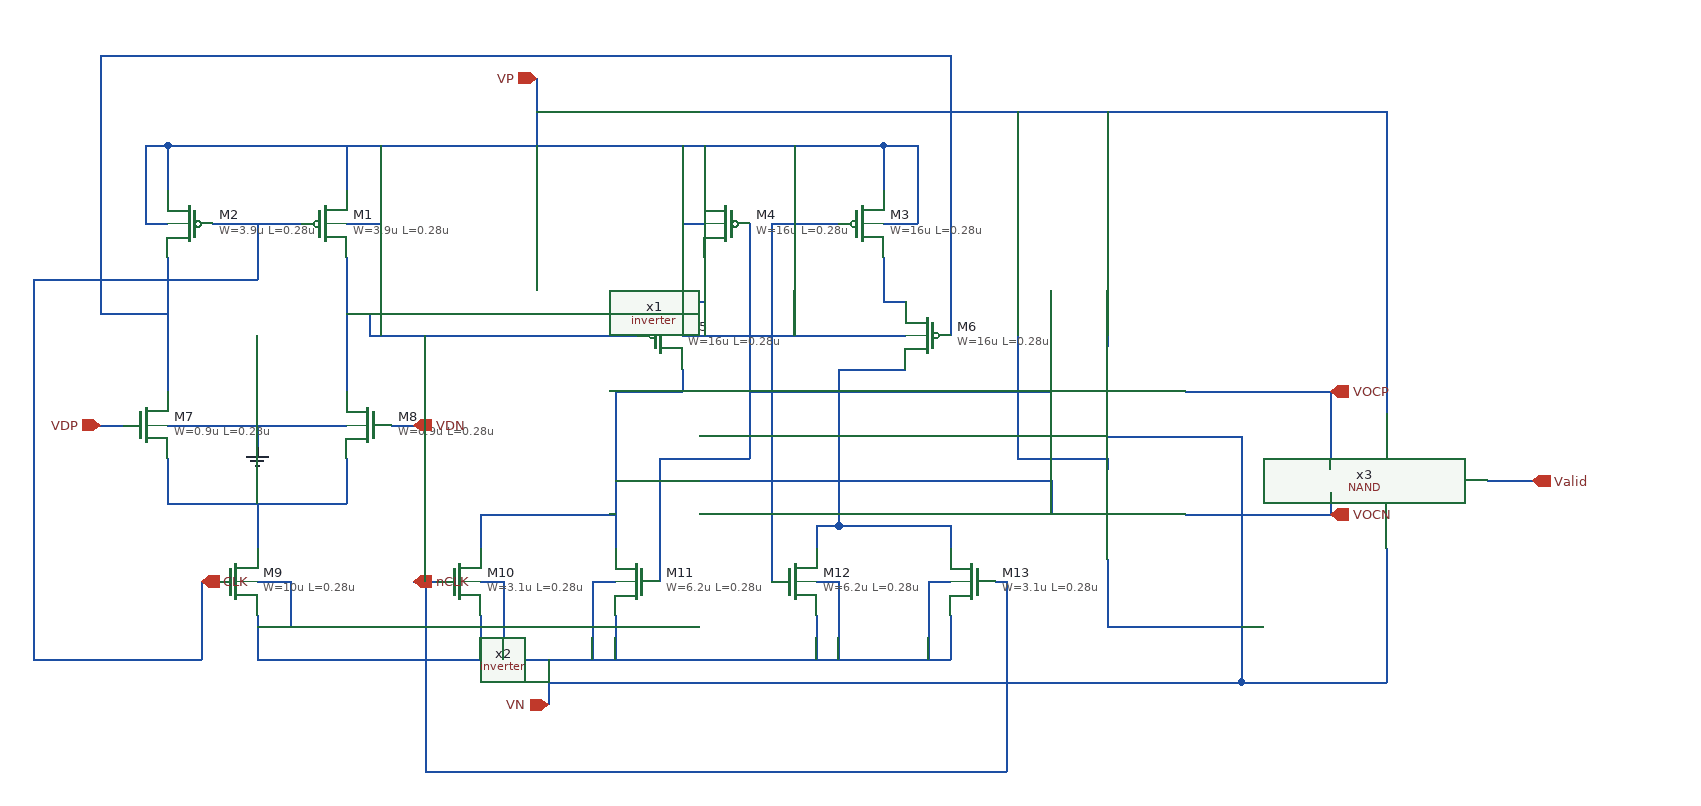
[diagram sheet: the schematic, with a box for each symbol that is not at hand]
v {xschem version=3.4.8RC file_version=1.2}
G {}
K {}
V {}
S {}
E {}
N 380 -920 380 -880 {lab=VP}
N 380 -920 1020 -920 {lab=VP}
N 1020 -920 1020 -880 {lab=VP}
N 540 -920 540 -880 {lab=VP}
N 540 -850 570 -850 {lab=VP}
N 570 -920 570 -850 {lab=VP}
N 860 -920 860 -880 {lab=VP}
N 840 -850 860 -850 {lab=VP}
N 840 -920 840 -850 {lab=VP}
N 1020 -850 1050 -850 {lab=VP}
N 1050 -920 1050 -850 {lab=VP}
N 1020 -920 1050 -920 {lab=VP}
N 710 -980 710 -920 {lab=VP}
N 840 -780 860 -780 {lab=#net1}
N 860 -820 860 -780 {lab=#net1}
N 1020 -820 1020 -780 {lab=#net2}
N 1020 -780 1040 -780 {lab=#net2}
N 420 -850 500 -850 {lab=CLK}
N 460 -850 460 -820 {lab=CLK}
N 380 -820 380 -700 {lab=#net3}
N 540 -820 540 -700 {lab=#net4}
N 380 -640 380 -600 {lab=#net5}
N 380 -600 540 -600 {lab=#net5}
N 540 -640 540 -600 {lab=#net5}
N 460 -600 460 -560 {lab=#net5}
N 460 -530 490 -530 {lab=VN}
N 490 -530 490 -490 {lab=VN}
N 460 -490 490 -490 {lab=VN}
N 460 -500 460 -460 {lab=VN}
N 660 -500 660 -460 {lab=VN}
N 780 -500 780 -460 {lab=VN}
N 960 -500 960 -460 {lab=VN}
N 1080 -500 1080 -460 {lab=VN}
N 460 -460 1080 -460 {lab=VN}
N 900 -850 900 -640 {lab=#net6}
N 820 -640 900 -640 {lab=#net6}
N 820 -640 820 -530 {lab=#net6}
N 920 -850 980 -850 {lab=#net7}
N 920 -850 920 -530 {lab=#net7}
N 720 -460 720 -420 {lab=VN}
N 760 -530 780 -530 {lab=VN}
N 760 -530 760 -460 {lab=VN}
N 660 -530 680 -530 {lab=VN}
N 680 -530 680 -460 {lab=VN}
N 960 -530 980 -530 {lab=VN}
N 980 -530 980 -460 {lab=VN}
N 1060 -530 1080 -530 {lab=VN}
N 1060 -530 1060 -460 {lab=VN}
N 840 -720 840 -700 {lab=#net7}
N 780 -700 840 -700 {lab=#net7}
N 780 -700 780 -560 {lab=#net7}
N 660 -590 660 -560 {lab=#net7}
N 660 -590 780 -590 {lab=#net7}
N 980 -720 1040 -720 {lab=#net6}
N 980 -720 980 -580 {lab=#net6}
N 960 -580 980 -580 {lab=#net6}
N 960 -580 960 -560 {lab=#net6}
N 980 -580 1080 -580 {lab=#net6}
N 1080 -580 1080 -560 {lab=#net6}
N 380 -670 540 -670 {lab=GND}
N 460 -670 460 -650 {lab=GND}
N 840 -750 1040 -750 {lab=VP}
N 1120 -530 1130 -530 {lab=nCLK}
N 410 -530 420 -530 {lab=CLK}
N 600 -530 620 -530 {lab=nCLK}
N 580 -670 600 -670 {lab=VDN}
N 320 -670 340 -670 {lab=VDP}
N 900 -700 980 -700 {lab=#net6}
N 980 -700 1170 -700 {lab=#net6}
N 780 -620 920 -620 {lab=#net7}
N 920 -620 1170 -620 {lab=#net7}
N 360 -770 380 -770 {lab=#net3}
N 540 -770 560 -770 {lab=#net4}
N 360 -850 380 -850 {lab=VP}
N 360 -920 360 -850 {lab=VP}
N 360 -920 380 -920 {lab=VP}
N 940 -920 940 -750 {lab=VP}
N 710 -950 1350 -950 {lab=VP}
N 610 -530 610 -360 {lab=nCLK}
N 610 -360 1130 -360 {lab=nCLK}
N 1130 -530 1130 -360 {lab=nCLK}
N 410 -530 410 -460 {lab=CLK}
N 260 -460 410 -460 {lab=CLK}
N 260 -800 260 -460 {lab=CLK}
N 260 -800 440 -800 {lab=CLK}
N 560 -770 560 -750 {lab=#net4}
N 320 -770 360 -770 {lab=#net3}
N 320 -1000 320 -770 {lab=#net3}
N 440 -800 460 -800 {lab=CLK}
N 460 -820 460 -800 {lab=CLK}
N 1170 -620 1170 -590 {lab=#net7}
N 1220 -950 1220 -740 {lab=VP}
N 1220 -640 1220 -630 {lab=VP}
N 1160 -640 1220 -640 {lab=VP}
N 1140 -640 1160 -640 {lab=VP}
N 1140 -950 1140 -640 {lab=VP}
N 1220 -660 1340 -660 {lab=VN}
N 1340 -660 1340 -440 {lab=VN}
N 1220 -550 1220 -490 {lab=VN}
N 1220 -490 1340 -490 {lab=VN}
N 720 -440 1340 -440 {lab=VN}
N 1290 -700 1420 -700 {lab=VOCP}
N 1420 -700 1420 -630 {lab=VOCP}
N 1290 -590 1420 -590 {lab=VOCN}
N 1420 -610 1420 -590 {lab=VOCN}
N 1560 -620 1600 -620 {lab=Valid}
N 1470 -950 1470 -680 {lab=VP}
N 1350 -950 1470 -950 {lab=VP}
N 1470 -560 1470 -440 {lab=VN}
N 1340 -440 1470 -440 {lab=VN}
N 560 -750 670 -750 {lab=#net4}
N 320 -1000 800 -1000 {lab=#net3}
N 670 -750 800 -750 {lab=#net4}
N 800 -1000 1080 -1000 {lab=#net3}
N 1080 -1000 1080 -750 {lab=#net3}
C {symbols/pfet_03v3.sym} 520 -850 0 0 {name=M1
L=0.28u
W=3.9u
nf=1
m=1
ad="'int((nf+1)/2) * W/nf * 0.18u'"
pd="'2*int((nf+1)/2) * (W/nf + 0.18u)'"
as="'int((nf+2)/2) * W/nf * 0.18u'"
ps="'2*int((nf+2)/2) * (W/nf + 0.18u)'"
nrd="'0.18u / W'" nrs="'0.18u / W'"
sa=0 sb=0 sd=0
model=pfet_03v3
spiceprefix=X
}
C {symbols/pfet_03v3.sym} 400 -850 0 1 {name=M2
L=0.28u
W=3.9u
nf=1
m=1
ad="'int((nf+1)/2) * W/nf * 0.18u'"
pd="'2*int((nf+1)/2) * (W/nf + 0.18u)'"
as="'int((nf+2)/2) * W/nf * 0.18u'"
ps="'2*int((nf+2)/2) * (W/nf + 0.18u)'"
nrd="'0.18u / W'" nrs="'0.18u / W'"
sa=0 sb=0 sd=0
model=pfet_03v3
spiceprefix=X
}
C {symbols/pfet_03v3.sym} 1000 -850 0 0 {name=M3
L=0.28u
W=16u
nf=1
m=1
ad="'int((nf+1)/2) * W/nf * 0.18u'"
pd="'2*int((nf+1)/2) * (W/nf + 0.18u)'"
as="'int((nf+2)/2) * W/nf * 0.18u'"
ps="'2*int((nf+2)/2) * (W/nf + 0.18u)'"
nrd="'0.18u / W'" nrs="'0.18u / W'"
sa=0 sb=0 sd=0
model=pfet_03v3
spiceprefix=X
}
C {symbols/pfet_03v3.sym} 880 -850 0 1 {name=M4
L=0.28u
W=16u
nf=1
m=1
ad="'int((nf+1)/2) * W/nf * 0.18u'"
pd="'2*int((nf+1)/2) * (W/nf + 0.18u)'"
as="'int((nf+2)/2) * W/nf * 0.18u'"
ps="'2*int((nf+2)/2) * (W/nf + 0.18u)'"
nrd="'0.18u / W'" nrs="'0.18u / W'"
sa=0 sb=0 sd=0
model=pfet_03v3
spiceprefix=X
}
C {symbols/pfet_03v3.sym} 820 -750 0 0 {name=M5
L=0.28u
W=16u
nf=1
m=1
ad="'int((nf+1)/2) * W/nf * 0.18u'"
pd="'2*int((nf+1)/2) * (W/nf + 0.18u)'"
as="'int((nf+2)/2) * W/nf * 0.18u'"
ps="'2*int((nf+2)/2) * (W/nf + 0.18u)'"
nrd="'0.18u / W'" nrs="'0.18u / W'"
sa=0 sb=0 sd=0
model=pfet_03v3
spiceprefix=X
}
C {symbols/pfet_03v3.sym} 1060 -750 0 1 {name=M6
L=0.28u
W=16u
nf=1
m=1
ad="'int((nf+1)/2) * W/nf * 0.18u'"
pd="'2*int((nf+1)/2) * (W/nf + 0.18u)'"
as="'int((nf+2)/2) * W/nf * 0.18u'"
ps="'2*int((nf+2)/2) * (W/nf + 0.18u)'"
nrd="'0.18u / W'" nrs="'0.18u / W'"
sa=0 sb=0 sd=0
model=pfet_03v3
spiceprefix=X
}
C {symbols/nfet_03v3.sym} 360 -670 0 0 {name=M7
L=0.28u
W=0.9u
nf=1
m=1
ad="'int((nf+1)/2) * W/nf * 0.18u'"
pd="'2*int((nf+1)/2) * (W/nf + 0.18u)'"
as="'int((nf+2)/2) * W/nf * 0.18u'"
ps="'2*int((nf+2)/2) * (W/nf + 0.18u)'"
nrd="'0.18u / W'" nrs="'0.18u / W'"
sa=0 sb=0 sd=0
model=nfet_03v3
spiceprefix=X
}
C {symbols/nfet_03v3.sym} 560 -670 0 1 {name=M8
L=0.28u
W=0.9u
nf=1
m=1
ad="'int((nf+1)/2) * W/nf * 0.18u'"
pd="'2*int((nf+1)/2) * (W/nf + 0.18u)'"
as="'int((nf+2)/2) * W/nf * 0.18u'"
ps="'2*int((nf+2)/2) * (W/nf + 0.18u)'"
nrd="'0.18u / W'" nrs="'0.18u / W'"
sa=0 sb=0 sd=0
model=nfet_03v3
spiceprefix=X
}
C {symbols/nfet_03v3.sym} 440 -530 0 0 {name=M9
L=0.28u
W=10u
nf=1
m=1
ad="'int((nf+1)/2) * W/nf * 0.18u'"
pd="'2*int((nf+1)/2) * (W/nf + 0.18u)'"
as="'int((nf+2)/2) * W/nf * 0.18u'"
ps="'2*int((nf+2)/2) * (W/nf + 0.18u)'"
nrd="'0.18u / W'" nrs="'0.18u / W'"
sa=0 sb=0 sd=0
model=nfet_03v3
spiceprefix=X
}
C {symbols/nfet_03v3.sym} 640 -530 0 0 {name=M10
L=0.28u
W=3.1u
nf=1
m=1
ad="'int((nf+1)/2) * W/nf * 0.18u'"
pd="'2*int((nf+1)/2) * (W/nf + 0.18u)'"
as="'int((nf+2)/2) * W/nf * 0.18u'"
ps="'2*int((nf+2)/2) * (W/nf + 0.18u)'"
nrd="'0.18u / W'" nrs="'0.18u / W'"
sa=0 sb=0 sd=0
model=nfet_03v3
spiceprefix=X
}
C {symbols/nfet_03v3.sym} 800 -530 0 1 {name=M11
L=0.28u
W=6.2u
nf=1
m=1
ad="'int((nf+1)/2) * W/nf * 0.18u'"
pd="'2*int((nf+1)/2) * (W/nf + 0.18u)'"
as="'int((nf+2)/2) * W/nf * 0.18u'"
ps="'2*int((nf+2)/2) * (W/nf + 0.18u)'"
nrd="'0.18u / W'" nrs="'0.18u / W'"
sa=0 sb=0 sd=0
model=nfet_03v3
spiceprefix=X
}
C {symbols/nfet_03v3.sym} 940 -530 0 0 {name=M12
L=0.28u
W=6.2u
nf=1
m=1
ad="'int((nf+1)/2) * W/nf * 0.18u'"
pd="'2*int((nf+1)/2) * (W/nf + 0.18u)'"
as="'int((nf+2)/2) * W/nf * 0.18u'"
ps="'2*int((nf+2)/2) * (W/nf + 0.18u)'"
nrd="'0.18u / W'" nrs="'0.18u / W'"
sa=0 sb=0 sd=0
model=nfet_03v3
spiceprefix=X
}
C {symbols/nfet_03v3.sym} 1100 -530 0 1 {name=M13
L=0.28u
W=3.1u
nf=1
m=1
ad="'int((nf+1)/2) * W/nf * 0.18u'"
pd="'2*int((nf+1)/2) * (W/nf + 0.18u)'"
as="'int((nf+2)/2) * W/nf * 0.18u'"
ps="'2*int((nf+2)/2) * (W/nf + 0.18u)'"
nrd="'0.18u / W'" nrs="'0.18u / W'"
sa=0 sb=0 sd=0
model=nfet_03v3
spiceprefix=X
}
C {gnd.sym} 460 -650 0 0 {name=l2 lab=GND}
C {iopin.sym} 710 -980 0 0 {name=p1 lab=VP}
C {iopin.sym} 410 -530 0 1 {name=p5 lab=CLK}
C {iopin.sym} 600 -530 0 1 {name=p6 lab=nCLK}
C {NAND.sym} 1300 -420 0 0 {name=x3}
C {ipin.sym} 320 -670 0 0 {name=p9 lab=VDP}
C {ipin.sym} 600 -670 0 1 {name=p10 lab=VDN}
C {opin.sym} 1600 -620 0 0 {name=p11 lab=Valid}
C {opin.sym} 1420 -700 3 0 {name=p16 lab=VOCP}
C {opin.sym} 1420 -590 1 0 {name=p17 lab=VOCN}
C {inverter.sym} 1140 -530 0 0 {name=x1}
C {inverter.sym} 1140 -420 0 0 {name=x2}
C {iopin.sym} 720 -420 0 0 {name=p2 lab=VN}
